One B-rep face of a CAD part: STEP entity #194.
In plain terms, the planar face has unit normal (1, 0, 0).
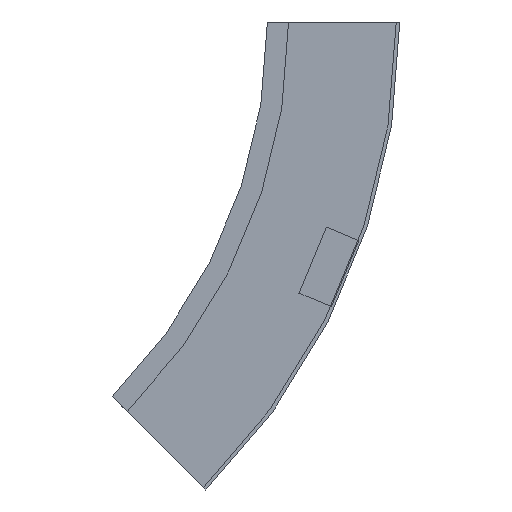
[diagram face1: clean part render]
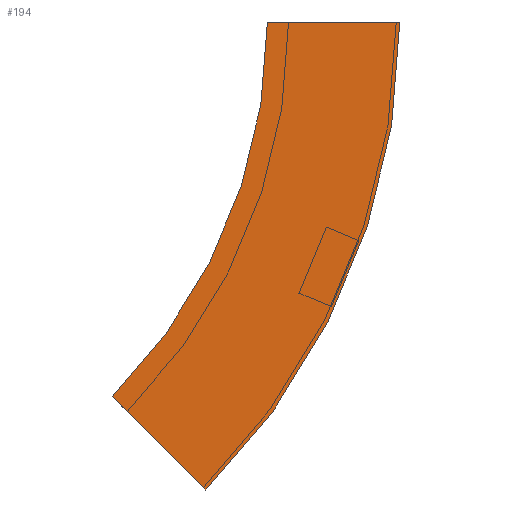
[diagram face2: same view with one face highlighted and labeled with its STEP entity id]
Its self-contained STEP definition (entity closure, numbers rounded to 3 decimals):
#3 = EDGE_CURVE ( 'NONE', #278, #369, #175, .T. ) ;
#6 = AXIS2_PLACEMENT_3D ( 'NONE', #79, #303, #532 ) ;
#23 = DIRECTION ( 'NONE',  ( 1., 0., 0. ) ) ;
#40 = DIRECTION ( 'NONE',  ( 0., 1., 0. ) ) ;
#46 = CARTESIAN_POINT ( 'NONE',  ( 0., -75., 0. ) ) ;
#68 = EDGE_LOOP ( 'NONE', ( #498, #363, #352, #284 ) ) ;
#79 = CARTESIAN_POINT ( 'NONE',  ( 0., 300., 0. ) ) ;
#117 = EDGE_CURVE ( 'NONE', #492, #341, #307, .T. ) ;
#118 = CARTESIAN_POINT ( 'NONE',  ( 0., 34.835, -265.165 ) ) ;
#137 = FACE_OUTER_BOUND ( 'NONE', #68, .T. ) ;
#149 = PLANE ( 'NONE',  #328 ) ;
#158 = CARTESIAN_POINT ( 'NONE',  ( 0., 300., 0. ) ) ;
#175 = LINE ( 'NONE', #118, #527 ) ;
#185 = EDGE_CURVE ( 'NONE', #492, #278, #251, .T. ) ;
#194 = ADVANCED_FACE ( 'NONE', ( #137 ), #149, .F. ) ;
#245 = CARTESIAN_POINT ( 'NONE',  ( 0., 87.868, -212.132 ) ) ;
#251 = CIRCLE ( 'NONE', #6, 375. ) ;
#256 = CARTESIAN_POINT ( 'NONE',  ( 0., -75., 0. ) ) ;
#270 = DIRECTION ( 'NONE',  ( -1., 0., 0. ) ) ;
#278 = VERTEX_POINT ( 'NONE', #372 ) ;
#284 = ORIENTED_EDGE ( 'NONE', *, *, #3, .T. ) ;
#287 = EDGE_CURVE ( 'NONE', #341, #369, #403, .T. ) ;
#291 = AXIS2_PLACEMENT_3D ( 'NONE', #158, #23, #505 ) ;
#303 = DIRECTION ( 'NONE',  ( 1., 0., 0. ) ) ;
#307 = LINE ( 'NONE', #256, #357 ) ;
#328 = AXIS2_PLACEMENT_3D ( 'NONE', #46, #270, #489 ) ;
#341 = VERTEX_POINT ( 'NONE', #502 ) ;
#343 = CARTESIAN_POINT ( 'NONE',  ( 0., -75., 0. ) ) ;
#352 = ORIENTED_EDGE ( 'NONE', *, *, #185, .T. ) ;
#357 = VECTOR ( 'NONE', #40, 1000. ) ;
#363 = ORIENTED_EDGE ( 'NONE', *, *, #117, .F. ) ;
#369 = VERTEX_POINT ( 'NONE', #245 ) ;
#372 = CARTESIAN_POINT ( 'NONE',  ( 0., 34.835, -265.165 ) ) ;
#403 = CIRCLE ( 'NONE', #291, 300. ) ;
#441 = DIRECTION ( 'NONE',  ( 0., 0.707, 0.707 ) ) ;
#489 = DIRECTION ( 'NONE',  ( 0., 0., 1. ) ) ;
#492 = VERTEX_POINT ( 'NONE', #343 ) ;
#498 = ORIENTED_EDGE ( 'NONE', *, *, #287, .F. ) ;
#502 = CARTESIAN_POINT ( 'NONE',  ( 0., 0., 0. ) ) ;
#505 = DIRECTION ( 'NONE',  ( 0., -1., 0. ) ) ;
#527 = VECTOR ( 'NONE', #441, 1000. ) ;
#532 = DIRECTION ( 'NONE',  ( 0., -1., 0. ) ) ;
